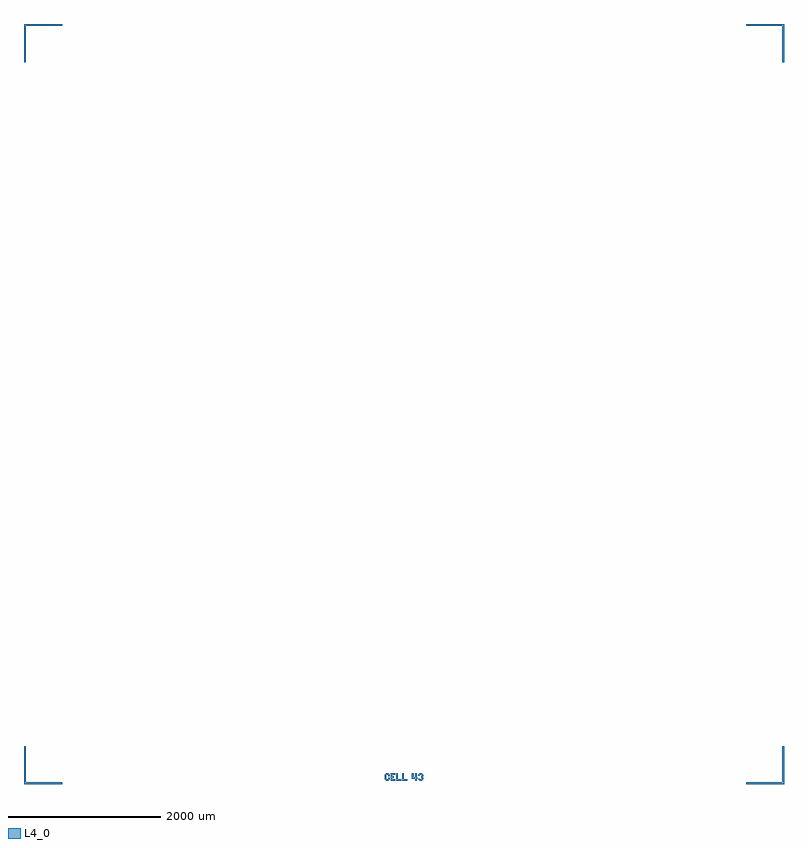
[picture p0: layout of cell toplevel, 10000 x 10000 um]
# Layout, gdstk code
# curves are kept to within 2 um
import gdstk
lib = gdstk.Library(unit=1e-6, precision=1e-09)
def P(c, l, *ps):  # polygons
    for p in ps: c.add(gdstk.Polygon(p, *l))
L4_0 = (4, 0)

toplevel = lib.new_cell('toplevel')
P(toplevel, L4_0, [(5000,5000),(5000,4500),(4980,4500),(4980,4980),(4500,4980),(4500,5000)],
  [(-5000,5000),(-5000,4500),(-4980,4500),(-4980,4980),(-4500,4980),(-4500,5000)],
  [(5000,-5000),(5000,-4500),(4980,-4500),(4980,-4980),(4500,-4980),(4500,-5000)],
  [(-5000,-5000),(-5000,-4500),(-4980,-4500),(-4980,-4980),(-4500,-4980),(-4500,-5000)],
  [(-235,-4960),(-255,-4940),(-255,-4880),(-235,-4860),(-205,-4860),(-185,-4880),(-185,-4900),(-205,-4900),(-205,-4890),(-215,-4880),(-225,-4880),(-235,-4890),(-235,-4930),(-225,-4940),(-215,-4940),(-205,-4930),(-205,-4920),(-185,-4920),(-185,-4940),(-205,-4960)],
  [(-115,-4860),(-115,-4880),(-155,-4880),(-155,-4900),(-135,-4900),(-135,-4920),(-155,-4920),(-155,-4940),(-115,-4940),(-115,-4960),(-175,-4960),(-175,-4860),(-115,-4860)],
  [(-105,-4860),(-85,-4860),(-85,-4940),(-35,-4940),(-35,-4960),(-105,-4960),(-105,-4860)],
  [(-25,-4860),(-5,-4860),(-5,-4940),(45,-4940),(45,-4960),(-25,-4960),(-25,-4860)],
  [(175,-4910),(175,-4930),(165,-4930),(165,-4960),(145,-4960),(145,-4930),(105,-4930),(105,-4860),(125,-4860),(125,-4910),(145,-4910),(145,-4860),(165,-4860),(165,-4910),(175,-4910)],
  [(235,-4860),(255,-4880),(255,-4900),(245,-4910),(255,-4920),(255,-4940),(235,-4960),(205,-4960),(185,-4940),(185,-4930),(205,-4930),(215,-4940),(225,-4940),(235,-4930),(225,-4920),(225,-4900),(235,-4890),(225,-4880),(215,-4880),(205,-4890),(185,-4890),(185,-4880),(205,-4860)])

lib.write_gds('toplevel.gds')
